VERSION 5.4 ;
NAMESCASESENSITIVE ON ;
BUSBITCHARS "[]" ;
DIVIDERCHAR "/" ;
UNITS
  DATABASE MICRONS 2000 ;
END UNITS
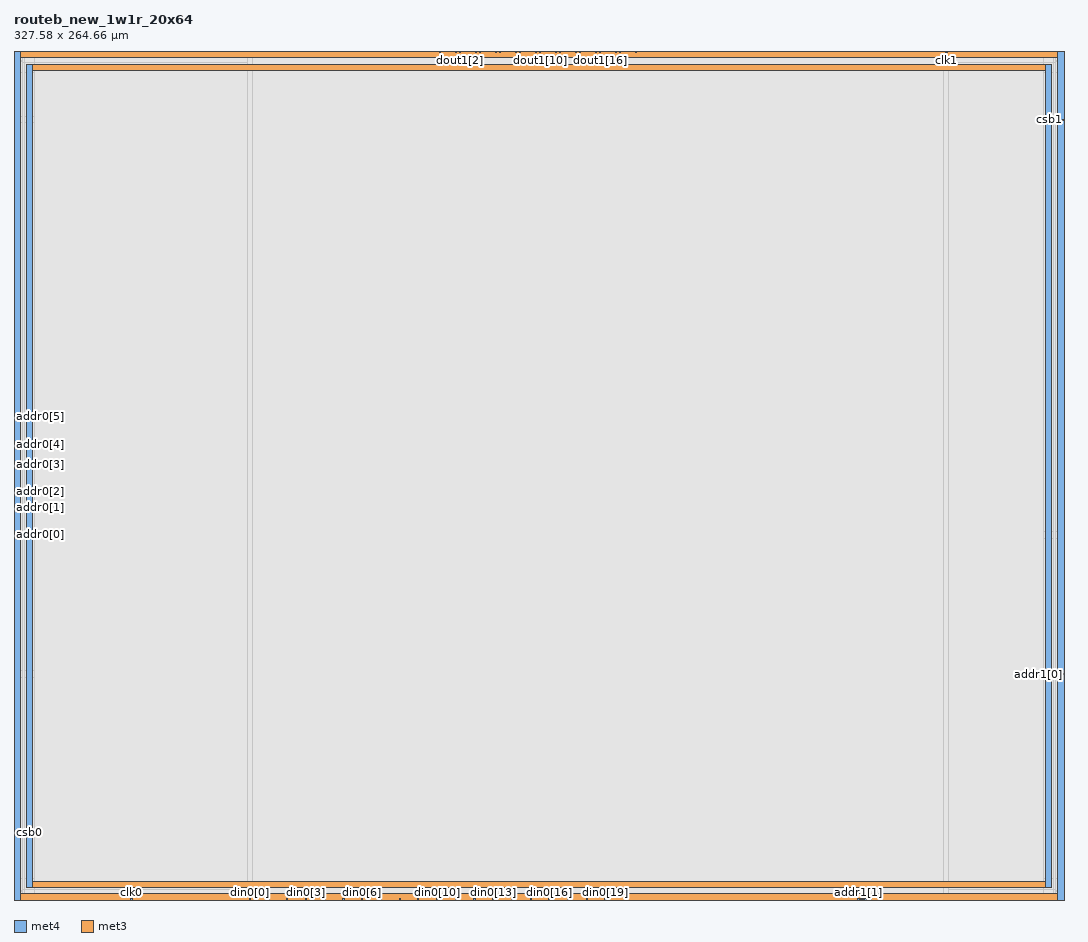
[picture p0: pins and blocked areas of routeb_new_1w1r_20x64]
MACRO routeb_new_1w1r_20x64
   CLASS BLOCK ;
   SIZE 327.58 BY 264.66 ;
   SYMMETRY X Y R90 ;
   PIN din0[0]
      DIRECTION INPUT ;
      PORT
         LAYER met4 ;
         RECT  73.4 0.0 73.78 0.38 ;
      END
   END din0[0]
   PIN din0[1]
      DIRECTION INPUT ;
      PORT
         LAYER met4 ;
         RECT  79.24 0.0 79.62 0.38 ;
      END
   END din0[1]
   PIN din0[2]
      DIRECTION INPUT ;
      PORT
         LAYER met4 ;
         RECT  85.08 0.0 85.46 0.38 ;
      END
   END din0[2]
   PIN din0[3]
      DIRECTION INPUT ;
      PORT
         LAYER met4 ;
         RECT  90.92 0.0 91.3 0.38 ;
      END
   END din0[3]
   PIN din0[4]
      DIRECTION INPUT ;
      PORT
         LAYER met4 ;
         RECT  96.76 0.0 97.14 0.38 ;
      END
   END din0[4]
   PIN din0[5]
      DIRECTION INPUT ;
      PORT
         LAYER met4 ;
         RECT  102.6 0.0 102.98 0.38 ;
      END
   END din0[5]
   PIN din0[6]
      DIRECTION INPUT ;
      PORT
         LAYER met4 ;
         RECT  108.44 0.0 108.82 0.38 ;
      END
   END din0[6]
   PIN din0[7]
      DIRECTION INPUT ;
      PORT
         LAYER met4 ;
         RECT  114.28 0.0 114.66 0.38 ;
      END
   END din0[7]
   PIN din0[8]
      DIRECTION INPUT ;
      PORT
         LAYER met4 ;
         RECT  120.12 0.0 120.5 0.38 ;
      END
   END din0[8]
   PIN din0[9]
      DIRECTION INPUT ;
      PORT
         LAYER met4 ;
         RECT  125.96 0.0 126.34 0.38 ;
      END
   END din0[9]
   PIN din0[10]
      DIRECTION INPUT ;
      PORT
         LAYER met4 ;
         RECT  131.8 0.0 132.18 0.38 ;
      END
   END din0[10]
   PIN din0[11]
      DIRECTION INPUT ;
      PORT
         LAYER met4 ;
         RECT  137.64 0.0 138.02 0.38 ;
      END
   END din0[11]
   PIN din0[12]
      DIRECTION INPUT ;
      PORT
         LAYER met4 ;
         RECT  143.48 0.0 143.86 0.38 ;
      END
   END din0[12]
   PIN din0[13]
      DIRECTION INPUT ;
      PORT
         LAYER met4 ;
         RECT  149.32 0.0 149.7 0.38 ;
      END
   END din0[13]
   PIN din0[14]
      DIRECTION INPUT ;
      PORT
         LAYER met4 ;
         RECT  155.16 0.0 155.54 0.38 ;
      END
   END din0[14]
   PIN din0[15]
      DIRECTION INPUT ;
      PORT
         LAYER met4 ;
         RECT  161.0 0.0 161.38 0.38 ;
      END
   END din0[15]
   PIN din0[16]
      DIRECTION INPUT ;
      PORT
         LAYER met4 ;
         RECT  166.84 0.0 167.22 0.38 ;
      END
   END din0[16]
   PIN din0[17]
      DIRECTION INPUT ;
      PORT
         LAYER met4 ;
         RECT  172.68 0.0 173.06 0.38 ;
      END
   END din0[17]
   PIN din0[18]
      DIRECTION INPUT ;
      PORT
         LAYER met4 ;
         RECT  178.52 0.0 178.9 0.38 ;
      END
   END din0[18]
   PIN din0[19]
      DIRECTION INPUT ;
      PORT
         LAYER met4 ;
         RECT  184.36 0.0 184.74 0.38 ;
      END
   END din0[19]
   PIN addr0[0]
      DIRECTION INPUT ;
      PORT
         LAYER met3 ;
         RECT  0.0 113.72 0.38 114.1 ;
      END
   END addr0[0]
   PIN addr0[1]
      DIRECTION INPUT ;
      PORT
         LAYER met3 ;
         RECT  0.0 122.22 0.38 122.6 ;
      END
   END addr0[1]
   PIN addr0[2]
      DIRECTION INPUT ;
      PORT
         LAYER met3 ;
         RECT  0.0 127.385 0.38 127.765 ;
      END
   END addr0[2]
   PIN addr0[3]
      DIRECTION INPUT ;
      PORT
         LAYER met3 ;
         RECT  0.0 135.785 0.38 136.165 ;
      END
   END addr0[3]
   PIN addr0[4]
      DIRECTION INPUT ;
      PORT
         LAYER met3 ;
         RECT  0.0 142.0 0.38 142.38 ;
      END
   END addr0[4]
   PIN addr0[5]
      DIRECTION INPUT ;
      PORT
         LAYER met3 ;
         RECT  0.0 150.5 0.38 150.88 ;
      END
   END addr0[5]
   PIN addr1[0]
      DIRECTION INPUT ;
      PORT
         LAYER met3 ;
         RECT  327.2 70.275 327.58 70.655 ;
      END
   END addr1[0]
   PIN addr1[1]
      DIRECTION INPUT ;
      PORT
         LAYER met4 ;
         RECT  263.255 0.0 263.635 0.38 ;
      END
   END addr1[1]
   PIN addr1[2]
      DIRECTION INPUT ;
      PORT
         LAYER met4 ;
         RECT  267.02 0.0 267.4 0.38 ;
      END
   END addr1[2]
   PIN addr1[3]
      DIRECTION INPUT ;
      PORT
         LAYER met4 ;
         RECT  263.945 0.0 264.325 0.38 ;
      END
   END addr1[3]
   PIN addr1[4]
      DIRECTION INPUT ;
      PORT
         LAYER met4 ;
         RECT  264.635 0.0 265.015 0.38 ;
      END
   END addr1[4]
   PIN addr1[5]
      DIRECTION INPUT ;
      PORT
         LAYER met4 ;
         RECT  265.48 0.0 265.86 0.38 ;
      END
   END addr1[5]
   PIN csb0
      DIRECTION INPUT ;
      PORT
         LAYER met3 ;
         RECT  0.0 21.01 0.38 21.39 ;
      END
   END csb0
   PIN csb1
      DIRECTION INPUT ;
      PORT
         LAYER met3 ;
         RECT  327.2 243.27 327.58 243.65 ;
      END
   END csb1
   PIN clk0
      DIRECTION INPUT ;
      PORT
         LAYER met4 ;
         RECT  36.5 0.0 36.88 0.38 ;
      END
   END clk0
   PIN clk1
      DIRECTION INPUT ;
      PORT
         LAYER met4 ;
         RECT  290.7 264.28 291.08 264.66 ;
      END
   END clk1
   PIN dout1[0]
      DIRECTION OUTPUT ;
      PORT
         LAYER met4 ;
         RECT  132.825 264.28 133.205 264.66 ;
      END
   END dout1[0]
   PIN dout1[1]
      DIRECTION OUTPUT ;
      PORT
         LAYER met4 ;
         RECT  137.795 264.28 138.175 264.66 ;
      END
   END dout1[1]
   PIN dout1[2]
      DIRECTION OUTPUT ;
      PORT
         LAYER met4 ;
         RECT  139.065 264.28 139.445 264.66 ;
      END
   END dout1[2]
   PIN dout1[3]
      DIRECTION OUTPUT ;
      PORT
         LAYER met4 ;
         RECT  144.035 264.28 144.415 264.66 ;
      END
   END dout1[3]
   PIN dout1[4]
      DIRECTION OUTPUT ;
      PORT
         LAYER met4 ;
         RECT  145.305 264.28 145.685 264.66 ;
      END
   END dout1[4]
   PIN dout1[5]
      DIRECTION OUTPUT ;
      PORT
         LAYER met4 ;
         RECT  150.275 264.28 150.655 264.66 ;
      END
   END dout1[5]
   PIN dout1[6]
      DIRECTION OUTPUT ;
      PORT
         LAYER met4 ;
         RECT  151.545 264.28 151.925 264.66 ;
      END
   END dout1[6]
   PIN dout1[7]
      DIRECTION OUTPUT ;
      PORT
         LAYER met4 ;
         RECT  156.515 264.28 156.895 264.66 ;
      END
   END dout1[7]
   PIN dout1[8]
      DIRECTION OUTPUT ;
      PORT
         LAYER met4 ;
         RECT  157.785 264.28 158.165 264.66 ;
      END
   END dout1[8]
   PIN dout1[9]
      DIRECTION OUTPUT ;
      PORT
         LAYER met4 ;
         RECT  162.755 264.28 163.135 264.66 ;
      END
   END dout1[9]
   PIN dout1[10]
      DIRECTION OUTPUT ;
      PORT
         LAYER met4 ;
         RECT  164.025 264.28 164.405 264.66 ;
      END
   END dout1[10]
   PIN dout1[11]
      DIRECTION OUTPUT ;
      PORT
         LAYER met4 ;
         RECT  168.995 264.28 169.375 264.66 ;
      END
   END dout1[11]
   PIN dout1[12]
      DIRECTION OUTPUT ;
      PORT
         LAYER met4 ;
         RECT  170.265 264.28 170.645 264.66 ;
      END
   END dout1[12]
   PIN dout1[13]
      DIRECTION OUTPUT ;
      PORT
         LAYER met4 ;
         RECT  175.235 264.28 175.615 264.66 ;
      END
   END dout1[13]
   PIN dout1[14]
      DIRECTION OUTPUT ;
      PORT
         LAYER met4 ;
         RECT  176.505 264.28 176.885 264.66 ;
      END
   END dout1[14]
   PIN dout1[15]
      DIRECTION OUTPUT ;
      PORT
         LAYER met4 ;
         RECT  181.475 264.28 181.855 264.66 ;
      END
   END dout1[15]
   PIN dout1[16]
      DIRECTION OUTPUT ;
      PORT
         LAYER met4 ;
         RECT  182.745 264.28 183.125 264.66 ;
      END
   END dout1[16]
   PIN dout1[17]
      DIRECTION OUTPUT ;
      PORT
         LAYER met4 ;
         RECT  187.715 264.28 188.095 264.66 ;
      END
   END dout1[17]
   PIN dout1[18]
      DIRECTION OUTPUT ;
      PORT
         LAYER met4 ;
         RECT  188.985 264.28 189.365 264.66 ;
      END
   END dout1[18]
   PIN dout1[19]
      DIRECTION OUTPUT ;
      PORT
         LAYER met4 ;
         RECT  193.955 264.28 194.335 264.66 ;
      END
   END dout1[19]
   PIN vccd1
      DIRECTION INOUT ;
      USE POWER ; 
      SHAPE ABUTMENT ; 
      PORT
         LAYER met3 ;
         RECT  0.0 0.0 327.58 1.94 ;
         LAYER met3 ;
         RECT  0.0 262.72 327.58 264.66 ;
         LAYER met4 ;
         RECT  325.64 0.0 327.58 264.66 ;
         LAYER met4 ;
         RECT  0.0 0.0 1.94 264.66 ;
      END
   END vccd1
   PIN vssd1
      DIRECTION INOUT ;
      USE GROUND ; 
      SHAPE ABUTMENT ; 
      PORT
         LAYER met4 ;
         RECT  3.88 3.88 5.82 260.78 ;
         LAYER met4 ;
         RECT  321.76 3.88 323.7 260.78 ;
         LAYER met3 ;
         RECT  3.88 258.84 323.7 260.78 ;
         LAYER met3 ;
         RECT  3.88 3.88 323.7 5.82 ;
      END
   END vssd1
   OBS
   LAYER  met1 ;
      RECT  0.72 0.72 326.86 263.94 ;
   LAYER  met2 ;
      RECT  0.72 0.72 326.86 263.94 ;
   LAYER  met3 ;
      RECT  1.18 112.92 326.86 114.9 ;
      RECT  0.72 114.9 1.18 121.42 ;
      RECT  0.72 123.4 1.18 126.585 ;
      RECT  0.72 128.565 1.18 134.985 ;
      RECT  0.72 136.965 1.18 141.2 ;
      RECT  0.72 143.18 1.18 149.7 ;
      RECT  1.18 69.475 326.4 71.455 ;
      RECT  1.18 71.455 326.4 112.92 ;
      RECT  326.4 71.455 326.86 112.92 ;
      RECT  0.72 22.19 1.18 112.92 ;
      RECT  1.18 114.9 326.4 242.47 ;
      RECT  1.18 242.47 326.4 244.45 ;
      RECT  326.4 114.9 326.86 242.47 ;
      RECT  326.4 2.74 326.86 69.475 ;
      RECT  0.72 2.74 1.18 20.21 ;
      RECT  0.72 151.68 1.18 261.92 ;
      RECT  326.4 244.45 326.86 261.92 ;
      RECT  1.18 244.45 3.08 258.04 ;
      RECT  1.18 258.04 3.08 261.58 ;
      RECT  1.18 261.58 3.08 261.92 ;
      RECT  3.08 244.45 324.5 258.04 ;
      RECT  3.08 261.58 324.5 261.92 ;
      RECT  324.5 244.45 326.4 258.04 ;
      RECT  324.5 258.04 326.4 261.58 ;
      RECT  324.5 261.58 326.4 261.92 ;
      RECT  1.18 2.74 3.08 3.08 ;
      RECT  1.18 3.08 3.08 6.62 ;
      RECT  1.18 6.62 3.08 69.475 ;
      RECT  3.08 2.74 324.5 3.08 ;
      RECT  3.08 6.62 324.5 69.475 ;
      RECT  324.5 2.74 326.4 3.08 ;
      RECT  324.5 3.08 326.4 6.62 ;
      RECT  324.5 6.62 326.4 69.475 ;
   LAYER  met4 ;
      RECT  72.8 0.98 74.38 263.94 ;
      RECT  74.38 0.72 78.64 0.98 ;
      RECT  80.22 0.72 84.48 0.98 ;
      RECT  86.06 0.72 90.32 0.98 ;
      RECT  91.9 0.72 96.16 0.98 ;
      RECT  97.74 0.72 102.0 0.98 ;
      RECT  103.58 0.72 107.84 0.98 ;
      RECT  109.42 0.72 113.68 0.98 ;
      RECT  115.26 0.72 119.52 0.98 ;
      RECT  121.1 0.72 125.36 0.98 ;
      RECT  126.94 0.72 131.2 0.98 ;
      RECT  132.78 0.72 137.04 0.98 ;
      RECT  138.62 0.72 142.88 0.98 ;
      RECT  144.46 0.72 148.72 0.98 ;
      RECT  150.3 0.72 154.56 0.98 ;
      RECT  156.14 0.72 160.4 0.98 ;
      RECT  161.98 0.72 166.24 0.98 ;
      RECT  167.82 0.72 172.08 0.98 ;
      RECT  173.66 0.72 177.92 0.98 ;
      RECT  179.5 0.72 183.76 0.98 ;
      RECT  185.34 0.72 262.655 0.98 ;
      RECT  37.48 0.72 72.8 0.98 ;
      RECT  74.38 0.98 290.1 263.68 ;
      RECT  290.1 0.98 291.68 263.68 ;
      RECT  74.38 263.68 132.225 263.94 ;
      RECT  133.805 263.68 137.195 263.94 ;
      RECT  140.045 263.68 143.435 263.94 ;
      RECT  146.285 263.68 149.675 263.94 ;
      RECT  152.525 263.68 155.915 263.94 ;
      RECT  158.765 263.68 162.155 263.94 ;
      RECT  165.005 263.68 168.395 263.94 ;
      RECT  171.245 263.68 174.635 263.94 ;
      RECT  177.485 263.68 180.875 263.94 ;
      RECT  183.725 263.68 187.115 263.94 ;
      RECT  189.965 263.68 193.355 263.94 ;
      RECT  194.935 263.68 290.1 263.94 ;
      RECT  268.0 0.72 325.04 0.98 ;
      RECT  291.68 263.68 325.04 263.94 ;
      RECT  2.54 0.72 35.9 0.98 ;
      RECT  2.54 0.98 3.28 3.28 ;
      RECT  2.54 3.28 3.28 261.38 ;
      RECT  2.54 261.38 3.28 263.94 ;
      RECT  3.28 0.98 6.42 3.28 ;
      RECT  3.28 261.38 6.42 263.94 ;
      RECT  6.42 0.98 72.8 3.28 ;
      RECT  6.42 3.28 72.8 261.38 ;
      RECT  6.42 261.38 72.8 263.94 ;
      RECT  291.68 0.98 321.16 3.28 ;
      RECT  291.68 3.28 321.16 261.38 ;
      RECT  291.68 261.38 321.16 263.68 ;
      RECT  321.16 0.98 324.3 3.28 ;
      RECT  321.16 261.38 324.3 263.68 ;
      RECT  324.3 0.98 325.04 3.28 ;
      RECT  324.3 3.28 325.04 261.38 ;
      RECT  324.3 261.38 325.04 263.68 ;
   END
END    routeb_new_1w1r_20x64
END    LIBRARY
